VERSION 5.7 ;
  NOWIREEXTENSIONATPIN ON ;
  DIVIDERCHAR "/" ;
  BUSBITCHARS "[]" ;
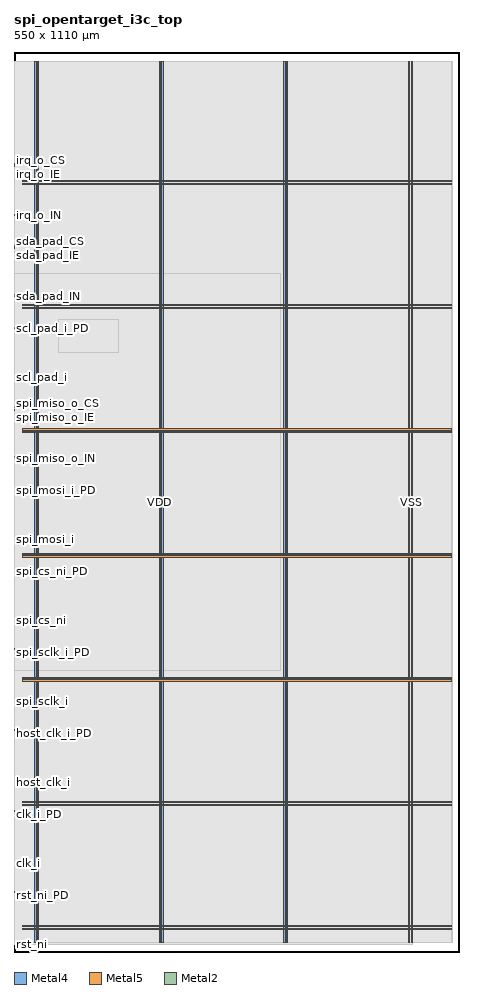
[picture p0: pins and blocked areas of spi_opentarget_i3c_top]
MACRO spi_opentarget_i3c_top
  CLASS BLOCK ;
  FOREIGN spi_opentarget_i3c_top ;
  ORIGIN 0.000 0.000 ;
  SIZE 550.000 BY 1110.000 ;
  PIN VDD
    DIRECTION INOUT ;
    USE POWER ;
    PORT
      LAYER Metal4 ;
        RECT 25.600 11.460 27.200 1097.900 ;
    END
    PORT
      LAYER Metal4 ;
        RECT 179.200 11.460 180.800 1097.900 ;
    END
    PORT
      LAYER Metal4 ;
        RECT 332.800 11.460 334.400 1097.900 ;
    END
    PORT
      LAYER Metal4 ;
        RECT 486.400 11.460 488.000 1097.900 ;
    END
    PORT
      LAYER Metal5 ;
        RECT 10.080 27.610 539.840 29.210 ;
    END
    PORT
      LAYER Metal5 ;
        RECT 10.080 180.790 539.840 182.390 ;
    END
    PORT
      LAYER Metal5 ;
        RECT 10.080 333.970 539.840 335.570 ;
    END
    PORT
      LAYER Metal5 ;
        RECT 10.080 487.150 539.840 488.750 ;
    END
    PORT
      LAYER Metal5 ;
        RECT 10.080 640.330 539.840 641.930 ;
    END
    PORT
      LAYER Metal5 ;
        RECT 10.080 793.510 539.840 795.110 ;
    END
    PORT
      LAYER Metal5 ;
        RECT 10.080 946.690 539.840 948.290 ;
    END
  END VDD
  PIN VSS
    DIRECTION INOUT ;
    USE GROUND ;
    PORT
      LAYER Metal4 ;
        RECT 28.900 11.460 30.500 1097.900 ;
    END
    PORT
      LAYER Metal4 ;
        RECT 182.500 11.460 184.100 1097.900 ;
    END
    PORT
      LAYER Metal4 ;
        RECT 336.100 11.460 337.700 1097.900 ;
    END
    PORT
      LAYER Metal4 ;
        RECT 489.700 11.460 491.300 1097.900 ;
    END
    PORT
      LAYER Metal5 ;
        RECT 10.080 30.910 539.840 32.510 ;
    END
    PORT
      LAYER Metal5 ;
        RECT 10.080 184.090 539.840 185.690 ;
    END
    PORT
      LAYER Metal5 ;
        RECT 10.080 337.270 539.840 338.870 ;
    END
    PORT
      LAYER Metal5 ;
        RECT 10.080 490.450 539.840 492.050 ;
    END
    PORT
      LAYER Metal5 ;
        RECT 10.080 643.630 539.840 645.230 ;
    END
    PORT
      LAYER Metal5 ;
        RECT 10.080 796.810 539.840 798.410 ;
    END
    PORT
      LAYER Metal5 ;
        RECT 10.080 949.990 539.840 951.590 ;
    END
  END VSS
  PIN clk_i
    DIRECTION INPUT ;
    USE SIGNAL ;
    ANTENNAGATEAREA 4.738000 ;
    PORT
      LAYER Metal2 ;
        RECT 0.000 108.760 1.000 109.140 ;
    END
  END clk_i
  PIN clk_i_PD
    DIRECTION OUTPUT ;
    USE SIGNAL ;
    ANTENNADIFFAREA 0.360800 ;
    PORT
      LAYER Metal2 ;
        RECT 0.000 169.290 1.000 169.670 ;
    END
  END clk_i_PD
  PIN clk_i_PU
    DIRECTION OUTPUT ;
    USE SIGNAL ;
    ANTENNADIFFAREA 0.360800 ;
    PORT
      LAYER Metal2 ;
        RECT 0.000 173.655 1.000 174.035 ;
    END
  END clk_i_PU
  PIN host_clk_i
    DIRECTION INPUT ;
    USE SIGNAL ;
    ANTENNAGATEAREA 4.738000 ;
    PORT
      LAYER Metal2 ;
        RECT 0.000 208.760 1.000 209.140 ;
    END
  END host_clk_i
  PIN host_clk_i_PD
    DIRECTION OUTPUT ;
    USE SIGNAL ;
    ANTENNADIFFAREA 0.360800 ;
    PORT
      LAYER Metal2 ;
        RECT 0.000 269.290 1.000 269.670 ;
    END
  END host_clk_i_PD
  PIN host_clk_i_PU
    DIRECTION OUTPUT ;
    USE SIGNAL ;
    ANTENNADIFFAREA 0.360800 ;
    PORT
      LAYER Metal2 ;
        RECT 0.000 273.655 1.000 274.035 ;
    END
  END host_clk_i_PU
  PIN irq_o_CS
    DIRECTION OUTPUT ;
    USE SIGNAL ;
    ANTENNADIFFAREA 0.360800 ;
    PORT
      LAYER Metal2 ;
        RECT 0.000 976.260 1.000 976.640 ;
    END
  END irq_o_CS
  PIN irq_o_IE
    DIRECTION OUTPUT ;
    USE SIGNAL ;
    ANTENNADIFFAREA 0.360800 ;
    PORT
      LAYER Metal2 ;
        RECT 0.000 968.235 1.000 968.615 ;
    END
  END irq_o_IE
  PIN irq_o_IN
    DIRECTION INPUT ;
    USE SIGNAL ;
    PORT
      LAYER Metal2 ;
        RECT 0.000 908.760 1.000 909.140 ;
    END
  END irq_o_IN
  PIN irq_o_OE
    DIRECTION OUTPUT ;
    USE SIGNAL ;
    ANTENNADIFFAREA 0.536800 ;
    PORT
      LAYER Metal2 ;
        RECT 0.000 909.490 1.000 909.870 ;
    END
  END irq_o_OE
  PIN irq_o_OUT
    DIRECTION OUTPUT ;
    USE SIGNAL ;
    ANTENNADIFFAREA 0.897600 ;
    PORT
      LAYER Metal2 ;
        RECT 0.000 910.220 1.000 910.600 ;
    END
  END irq_o_OUT
  PIN irq_o_PD
    DIRECTION OUTPUT ;
    USE SIGNAL ;
    ANTENNADIFFAREA 0.360800 ;
    PORT
      LAYER Metal2 ;
        RECT 0.000 969.290 1.000 969.670 ;
    END
  END irq_o_PD
  PIN irq_o_PDRV0
    DIRECTION OUTPUT ;
    USE SIGNAL ;
    ANTENNADIFFAREA 0.360800 ;
    PORT
      LAYER Metal2 ;
        RECT 0.000 972.510 1.000 972.890 ;
    END
  END irq_o_PDRV0
  PIN irq_o_PDRV1
    DIRECTION OUTPUT ;
    USE SIGNAL ;
    ANTENNADIFFAREA 0.360800 ;
    PORT
      LAYER Metal2 ;
        RECT 0.000 971.800 1.000 972.180 ;
    END
  END irq_o_PDRV1
  PIN irq_o_PU
    DIRECTION OUTPUT ;
    USE SIGNAL ;
    ANTENNADIFFAREA 0.360800 ;
    PORT
      LAYER Metal2 ;
        RECT 0.000 973.655 1.000 974.035 ;
    END
  END irq_o_PU
  PIN irq_o_SL
    DIRECTION OUTPUT ;
    USE SIGNAL ;
    ANTENNADIFFAREA 0.360800 ;
    PORT
      LAYER Metal2 ;
        RECT 0.000 910.950 1.000 911.330 ;
    END
  END irq_o_SL
  PIN rst_ni
    DIRECTION INPUT ;
    USE SIGNAL ;
    ANTENNAGATEAREA 0.396000 ;
    PORT
      LAYER Metal2 ;
        RECT 0.000 8.760 1.000 9.140 ;
    END
  END rst_ni
  PIN rst_ni_PD
    DIRECTION OUTPUT ;
    USE SIGNAL ;
    ANTENNADIFFAREA 0.360800 ;
    PORT
      LAYER Metal2 ;
        RECT 0.000 69.290 1.000 69.670 ;
    END
  END rst_ni_PD
  PIN rst_ni_PU
    DIRECTION OUTPUT ;
    USE SIGNAL ;
    ANTENNADIFFAREA 0.360800 ;
    PORT
      LAYER Metal2 ;
        RECT 0.000 73.655 1.000 74.035 ;
    END
  END rst_ni_PU
  PIN scl_pad_i
    DIRECTION INPUT ;
    USE SIGNAL ;
    ANTENNAGATEAREA 0.396000 ;
    PORT
      LAYER Metal2 ;
        RECT 0.000 708.760 1.000 709.140 ;
    END
  END scl_pad_i
  PIN scl_pad_i_PD
    DIRECTION OUTPUT ;
    USE SIGNAL ;
    ANTENNADIFFAREA 0.360800 ;
    PORT
      LAYER Metal2 ;
        RECT 0.000 769.290 1.000 769.670 ;
    END
  END scl_pad_i_PD
  PIN scl_pad_i_PU
    DIRECTION OUTPUT ;
    USE SIGNAL ;
    ANTENNADIFFAREA 0.360800 ;
    PORT
      LAYER Metal2 ;
        RECT 0.000 773.655 1.000 774.035 ;
    END
  END scl_pad_i_PU
  PIN sda_pad_CS
    DIRECTION OUTPUT ;
    USE SIGNAL ;
    ANTENNADIFFAREA 0.360800 ;
    PORT
      LAYER Metal2 ;
        RECT 0.000 876.260 1.000 876.640 ;
    END
  END sda_pad_CS
  PIN sda_pad_IE
    DIRECTION OUTPUT ;
    USE SIGNAL ;
    ANTENNADIFFAREA 0.536800 ;
    PORT
      LAYER Metal2 ;
        RECT 0.000 868.235 1.000 868.615 ;
    END
  END sda_pad_IE
  PIN sda_pad_IN
    DIRECTION INPUT ;
    USE SIGNAL ;
    ANTENNAGATEAREA 0.396000 ;
    PORT
      LAYER Metal2 ;
        RECT 0.000 808.760 1.000 809.140 ;
    END
  END sda_pad_IN
  PIN sda_pad_OUT
    DIRECTION OUTPUT ;
    USE SIGNAL ;
    ANTENNADIFFAREA 0.897600 ;
    PORT
      LAYER Metal2 ;
        RECT 0.000 810.220 1.000 810.600 ;
    END
  END sda_pad_OUT
  PIN sda_pad_PD
    DIRECTION OUTPUT ;
    USE SIGNAL ;
    ANTENNADIFFAREA 0.360800 ;
    PORT
      LAYER Metal2 ;
        RECT 0.000 869.290 1.000 869.670 ;
    END
  END sda_pad_PD
  PIN sda_pad_PDRV0
    DIRECTION OUTPUT ;
    USE SIGNAL ;
    ANTENNADIFFAREA 0.360800 ;
    PORT
      LAYER Metal2 ;
        RECT 0.000 872.510 1.000 872.890 ;
    END
  END sda_pad_PDRV0
  PIN sda_pad_PDRV1
    DIRECTION OUTPUT ;
    USE SIGNAL ;
    ANTENNADIFFAREA 0.360800 ;
    PORT
      LAYER Metal2 ;
        RECT 0.000 871.800 1.000 872.180 ;
    END
  END sda_pad_PDRV1
  PIN sda_pad_PU
    DIRECTION OUTPUT ;
    USE SIGNAL ;
    ANTENNADIFFAREA 0.360800 ;
    PORT
      LAYER Metal2 ;
        RECT 0.000 873.655 1.000 874.035 ;
    END
  END sda_pad_PU
  PIN sda_pad_SL
    DIRECTION OUTPUT ;
    USE SIGNAL ;
    ANTENNADIFFAREA 0.360800 ;
    PORT
      LAYER Metal2 ;
        RECT 0.000 810.950 1.000 811.330 ;
    END
  END sda_pad_SL
  PIN sda_pad_oe
    DIRECTION OUTPUT ;
    USE SIGNAL ;
    ANTENNADIFFAREA 0.897600 ;
    PORT
      LAYER Metal2 ;
        RECT 0.000 809.490 1.000 809.870 ;
    END
  END sda_pad_oe
  PIN spi_cs_ni
    DIRECTION INPUT ;
    USE SIGNAL ;
    ANTENNAGATEAREA 0.396000 ;
    PORT
      LAYER Metal2 ;
        RECT 0.000 408.760 1.000 409.140 ;
    END
  END spi_cs_ni
  PIN spi_cs_ni_PD
    DIRECTION OUTPUT ;
    USE SIGNAL ;
    ANTENNADIFFAREA 0.360800 ;
    PORT
      LAYER Metal2 ;
        RECT 0.000 469.290 1.000 469.670 ;
    END
  END spi_cs_ni_PD
  PIN spi_cs_ni_PU
    DIRECTION OUTPUT ;
    USE SIGNAL ;
    ANTENNADIFFAREA 0.360800 ;
    PORT
      LAYER Metal2 ;
        RECT 0.000 473.655 1.000 474.035 ;
    END
  END spi_cs_ni_PU
  PIN spi_miso_o_CS
    DIRECTION OUTPUT ;
    USE SIGNAL ;
    ANTENNADIFFAREA 0.360800 ;
    PORT
      LAYER Metal2 ;
        RECT 0.000 676.260 1.000 676.640 ;
    END
  END spi_miso_o_CS
  PIN spi_miso_o_IE
    DIRECTION OUTPUT ;
    USE SIGNAL ;
    ANTENNADIFFAREA 0.360800 ;
    PORT
      LAYER Metal2 ;
        RECT 0.000 668.235 1.000 668.615 ;
    END
  END spi_miso_o_IE
  PIN spi_miso_o_IN
    DIRECTION INPUT ;
    USE SIGNAL ;
    PORT
      LAYER Metal2 ;
        RECT 0.000 608.760 1.000 609.140 ;
    END
  END spi_miso_o_IN
  PIN spi_miso_o_OE
    DIRECTION OUTPUT ;
    USE SIGNAL ;
    ANTENNADIFFAREA 0.536800 ;
    PORT
      LAYER Metal2 ;
        RECT 0.000 609.490 1.000 609.870 ;
    END
  END spi_miso_o_OE
  PIN spi_miso_o_OUT
    DIRECTION OUTPUT ;
    USE SIGNAL ;
    ANTENNADIFFAREA 0.897600 ;
    PORT
      LAYER Metal2 ;
        RECT 0.000 610.220 1.000 610.600 ;
    END
  END spi_miso_o_OUT
  PIN spi_miso_o_PD
    DIRECTION OUTPUT ;
    USE SIGNAL ;
    ANTENNADIFFAREA 0.360800 ;
    PORT
      LAYER Metal2 ;
        RECT 0.000 669.290 1.000 669.670 ;
    END
  END spi_miso_o_PD
  PIN spi_miso_o_PDRV0
    DIRECTION OUTPUT ;
    USE SIGNAL ;
    ANTENNADIFFAREA 0.360800 ;
    PORT
      LAYER Metal2 ;
        RECT 0.000 672.510 1.000 672.890 ;
    END
  END spi_miso_o_PDRV0
  PIN spi_miso_o_PDRV1
    DIRECTION OUTPUT ;
    USE SIGNAL ;
    ANTENNADIFFAREA 0.360800 ;
    PORT
      LAYER Metal2 ;
        RECT 0.000 671.800 1.000 672.180 ;
    END
  END spi_miso_o_PDRV1
  PIN spi_miso_o_PU
    DIRECTION OUTPUT ;
    USE SIGNAL ;
    ANTENNADIFFAREA 0.360800 ;
    PORT
      LAYER Metal2 ;
        RECT 0.000 673.655 1.000 674.035 ;
    END
  END spi_miso_o_PU
  PIN spi_miso_o_SL
    DIRECTION OUTPUT ;
    USE SIGNAL ;
    ANTENNADIFFAREA 0.360800 ;
    PORT
      LAYER Metal2 ;
        RECT 0.000 610.950 1.000 611.330 ;
    END
  END spi_miso_o_SL
  PIN spi_mosi_i
    DIRECTION INPUT ;
    USE SIGNAL ;
    ANTENNAGATEAREA 0.396000 ;
    PORT
      LAYER Metal2 ;
        RECT 0.000 508.760 1.000 509.140 ;
    END
  END spi_mosi_i
  PIN spi_mosi_i_PD
    DIRECTION OUTPUT ;
    USE SIGNAL ;
    ANTENNADIFFAREA 0.360800 ;
    PORT
      LAYER Metal2 ;
        RECT 0.000 569.290 1.000 569.670 ;
    END
  END spi_mosi_i_PD
  PIN spi_mosi_i_PU
    DIRECTION OUTPUT ;
    USE SIGNAL ;
    ANTENNADIFFAREA 0.360800 ;
    PORT
      LAYER Metal2 ;
        RECT 0.000 573.655 1.000 574.035 ;
    END
  END spi_mosi_i_PU
  PIN spi_sclk_i
    DIRECTION INPUT ;
    USE SIGNAL ;
    ANTENNAGATEAREA 0.606000 ;
    PORT
      LAYER Metal2 ;
        RECT 0.000 308.760 1.000 309.140 ;
    END
  END spi_sclk_i
  PIN spi_sclk_i_PD
    DIRECTION OUTPUT ;
    USE SIGNAL ;
    ANTENNADIFFAREA 0.360800 ;
    PORT
      LAYER Metal2 ;
        RECT 0.000 369.290 1.000 369.670 ;
    END
  END spi_sclk_i_PD
  PIN spi_sclk_i_PU
    DIRECTION OUTPUT ;
    USE SIGNAL ;
    ANTENNADIFFAREA 0.360800 ;
    PORT
      LAYER Metal2 ;
        RECT 0.000 373.655 1.000 374.035 ;
    END
  END spi_sclk_i_PU
  OBS
      LAYER Nwell ;
        RECT 9.650 11.330 540.270 1098.030 ;
      LAYER Metal1 ;
        RECT 10.080 11.460 539.840 1097.900 ;
      LAYER Metal2 ;
        RECT 0.140 976.940 491.160 1097.790 ;
        RECT 1.300 975.960 491.160 976.940 ;
        RECT 0.140 974.335 491.160 975.960 ;
        RECT 1.300 973.355 491.160 974.335 ;
        RECT 0.140 973.190 491.160 973.355 ;
        RECT 1.300 971.500 491.160 973.190 ;
        RECT 0.140 969.970 491.160 971.500 ;
        RECT 1.300 968.990 491.160 969.970 ;
        RECT 0.140 968.915 491.160 968.990 ;
        RECT 1.300 967.935 491.160 968.915 ;
        RECT 0.140 911.630 491.160 967.935 ;
        RECT 1.300 908.460 491.160 911.630 ;
        RECT 0.140 876.940 491.160 908.460 ;
        RECT 1.300 875.960 491.160 876.940 ;
        RECT 0.140 874.335 491.160 875.960 ;
        RECT 1.300 873.355 491.160 874.335 ;
        RECT 0.140 873.190 491.160 873.355 ;
        RECT 1.300 871.500 491.160 873.190 ;
        RECT 0.140 869.970 491.160 871.500 ;
        RECT 1.300 868.990 491.160 869.970 ;
        RECT 0.140 868.915 491.160 868.990 ;
        RECT 1.300 867.935 491.160 868.915 ;
        RECT 0.140 811.630 491.160 867.935 ;
        RECT 1.300 808.460 491.160 811.630 ;
        RECT 0.140 774.335 491.160 808.460 ;
        RECT 1.300 773.355 491.160 774.335 ;
        RECT 0.140 769.970 491.160 773.355 ;
        RECT 1.300 768.990 491.160 769.970 ;
        RECT 0.140 709.440 491.160 768.990 ;
        RECT 1.300 708.460 491.160 709.440 ;
        RECT 0.140 676.940 491.160 708.460 ;
        RECT 1.300 675.960 491.160 676.940 ;
        RECT 0.140 674.335 491.160 675.960 ;
        RECT 1.300 673.355 491.160 674.335 ;
        RECT 0.140 673.190 491.160 673.355 ;
        RECT 1.300 671.500 491.160 673.190 ;
        RECT 0.140 669.970 491.160 671.500 ;
        RECT 1.300 668.990 491.160 669.970 ;
        RECT 0.140 668.915 491.160 668.990 ;
        RECT 1.300 667.935 491.160 668.915 ;
        RECT 0.140 611.630 491.160 667.935 ;
        RECT 1.300 608.460 491.160 611.630 ;
        RECT 0.140 574.335 491.160 608.460 ;
        RECT 1.300 573.355 491.160 574.335 ;
        RECT 0.140 569.970 491.160 573.355 ;
        RECT 1.300 568.990 491.160 569.970 ;
        RECT 0.140 509.440 491.160 568.990 ;
        RECT 1.300 508.460 491.160 509.440 ;
        RECT 0.140 474.335 491.160 508.460 ;
        RECT 1.300 473.355 491.160 474.335 ;
        RECT 0.140 469.970 491.160 473.355 ;
        RECT 1.300 468.990 491.160 469.970 ;
        RECT 0.140 409.440 491.160 468.990 ;
        RECT 1.300 408.460 491.160 409.440 ;
        RECT 0.140 374.335 491.160 408.460 ;
        RECT 1.300 373.355 491.160 374.335 ;
        RECT 0.140 369.970 491.160 373.355 ;
        RECT 1.300 368.990 491.160 369.970 ;
        RECT 0.140 309.440 491.160 368.990 ;
        RECT 1.300 308.460 491.160 309.440 ;
        RECT 0.140 274.335 491.160 308.460 ;
        RECT 1.300 273.355 491.160 274.335 ;
        RECT 0.140 269.970 491.160 273.355 ;
        RECT 1.300 268.990 491.160 269.970 ;
        RECT 0.140 209.440 491.160 268.990 ;
        RECT 1.300 208.460 491.160 209.440 ;
        RECT 0.140 174.335 491.160 208.460 ;
        RECT 1.300 173.355 491.160 174.335 ;
        RECT 0.140 169.970 491.160 173.355 ;
        RECT 1.300 168.990 491.160 169.970 ;
        RECT 0.140 109.440 491.160 168.990 ;
        RECT 1.300 108.460 491.160 109.440 ;
        RECT 0.140 74.335 491.160 108.460 ;
        RECT 1.300 73.355 491.160 74.335 ;
        RECT 0.140 69.970 491.160 73.355 ;
        RECT 1.300 68.990 491.160 69.970 ;
        RECT 0.140 9.440 491.160 68.990 ;
        RECT 1.300 9.140 491.160 9.440 ;
      LAYER Metal3 ;
        RECT 0.090 11.620 491.210 1097.740 ;
      LAYER Metal4 ;
        RECT 0.700 347.290 25.300 837.110 ;
        RECT 27.500 347.290 28.600 837.110 ;
        RECT 30.800 347.290 178.900 837.110 ;
        RECT 181.100 347.290 182.200 837.110 ;
        RECT 184.400 347.290 328.580 837.110 ;
      LAYER Metal5 ;
        RECT 54.940 739.130 128.740 780.070 ;
  END
END spi_opentarget_i3c_top
END LIBRARY

